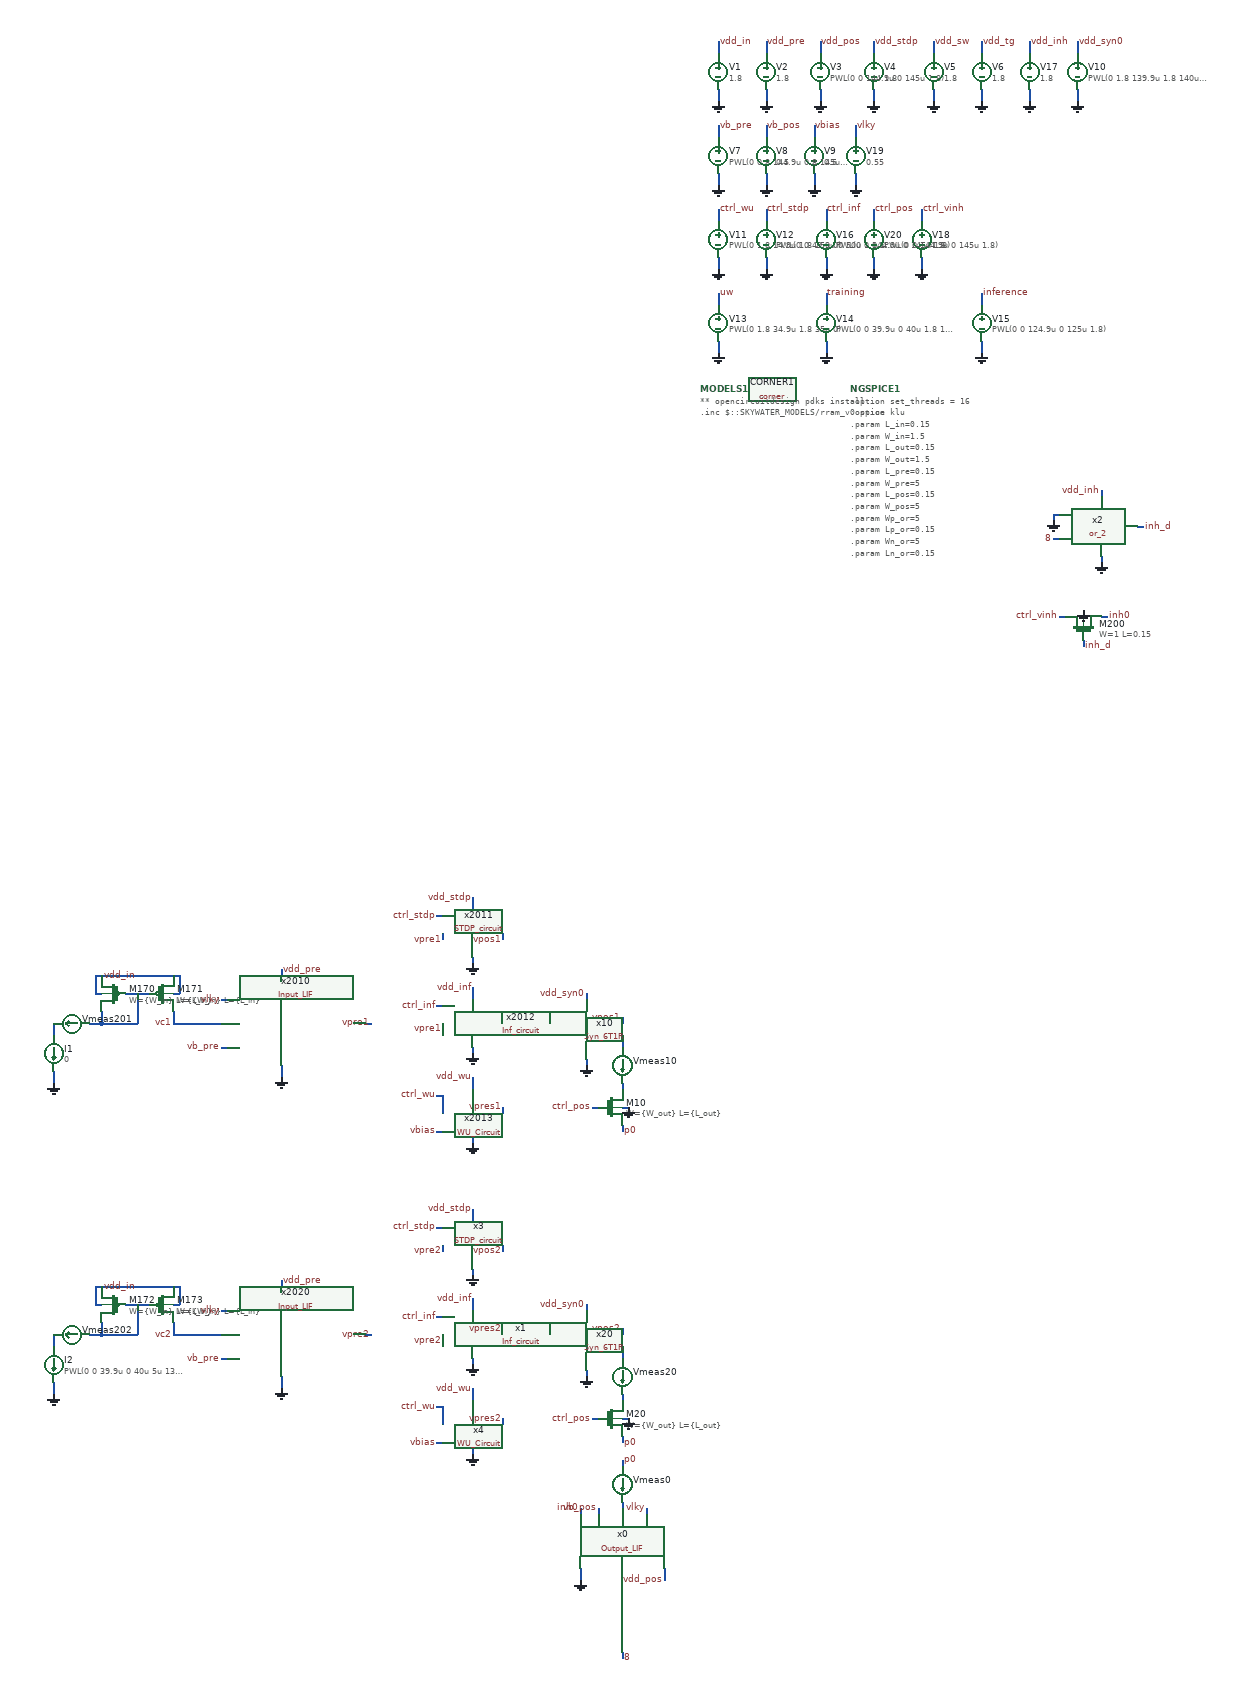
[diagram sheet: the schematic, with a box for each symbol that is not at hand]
v {xschem version=3.4.5 file_version=1.2
}
G {}
K {}
V {}
S {}
E {}
B 2 -1600 -1200 -800 -800 {flags=graph
y1=0.388
y2=2.403
ypos1=0
ypos2=2
divy=5
subdivy=1
unity=1
x1=-9.81196e-06
x2=0.000140188
divx=5
subdivx=1
xlabmag=1.0
ylabmag=1.0


dataset=-1
unitx=1
logx=0
logy=0




color="4 6 7 8 10 11 12 13 15"
node="\\"vpos1; vpos1\\"
\\"vpos2; vpos2\\"
\\"vpos3; vpos3\\"
\\"vpos4; vpos4\\"
\\"vpos5; vpos5\\"
\\"vpos6; vpos6\\"
\\"vpos7; vpos7\\"
\\"vpos8; vpos8\\"
\\"vpos9; vpos9\\""}
B 2 -800 -400 0 0 {flags=graph
y1=0
y2=1.8
ypos1=0
ypos2=2
divy=5
subdivy=1
unity=1
x1=-9.81196e-06
x2=0.000140188
divx=5
subdivx=1
xlabmag=1.0
ylabmag=1.0


dataset=-1
unitx=1
logx=0
logy=0
color="7 8 11"
node="\\"Update Weights;uw\\"
\\"Training;training\\"
\\"Inference;inference\\""}
B 2 0 -2400 800 -2000 {flags=graph
y1=-5.2e-07
y2=2.2e-05
ypos1=0
ypos2=2
divy=5
subdivy=1
unity=1
x1=-9.81196e-06
x2=0.000140188
divx=5
subdivx=1
xlabmag=1.0
ylabmag=1.0


dataset=-1
unitx=1
logx=0
logy=0






color="15 16 17"
node="\\"Ip0;i(vmeas0)\\"
\\"Ip1;i(vmeas1)\\"
\\"Ip2;i(vmeas2)\\""}
B 2 1600 -2400 2400 -2000 {flags=graph
y1=-8.4e-09
y2=1.9
ypos1=0
ypos2=2
divy=5
subdivy=1
unity=1
x1=-9.81196e-06
x2=0.000140188
divx=5
subdivx=1
xlabmag=1.0
ylabmag=1.0


dataset=-1
unitx=1
logx=0
logy=0




color=15
node=8}
B 2 -800 -1600 0 -1200 {flags=graph
y1=-0.0031
y2=1.9
ypos1=0
ypos2=2
divy=5
subdivy=1
unity=1
x1=-9.81196e-06
x2=0.000140188
divx=5
subdivx=1
xlabmag=1.0
ylabmag=1.0


dataset=-1
unitx=1
logx=0
logy=0



color="15 16 18"
node="inh0
inh1
inh2"}
B 2 -1600 -800 -800 -400 {flags=graph
y1=3
y2=4.9
ypos1=0
ypos2=2
divy=5
subdivy=1
unity=1
x1=-9.81196e-06
x2=0.000140188
divx=5
subdivx=1
xlabmag=1.0
ylabmag=1.0


dataset=-1
unitx=1
logx=0
logy=0





color="4 6 7 8 10 11 12 13 15 21 5 14 16 17 18 21"
node="\\"S10; 5 n.x10.xr1.n1#ngap -\\"
\\"S20; 5 n.x20.xr1.n1#ngap -\\"
\\"S30; 5 n.x30.xr1.n1#ngap -\\"
\\"S40; 5 n.x40.xr1.n1#ngap -\\"
\\"S50; 5 n.x50.xr1.n1#ngap -\\"
\\"S60; 5 n.x60.xr1.n1#ngap -\\"
\\"S70; 5 n.x70.xr1.n1#ngap -\\"
\\"S80; 5 n.x80.xr1.n1#ngap -\\"
\\"S90; 5 n.x90.xr1.n1#ngap -\\"
\\"S100; 5 n.x100.xr1.n1#ngap -\\"
\\"S110; 5 n.x110.xr1.n1#ngap -\\"
\\"S120; 5 n.x120.xr1.n1#ngap -\\"
\\"S130; 5 n.x130.xr1.n1#ngap -\\"
\\"S140; 5 n.x140.xr1.n1#ngap -\\"
\\"S150; 5 n.x150.xr1.n1#ngap -\\"
\\"[nm]\\""}
B 2 -800 -800 0 -400 {flags=graph
y1=-2.7e-06
y2=2.7e-06
ypos1=0
ypos2=2
divy=5
subdivy=1
unity=1
x1=-9.81196e-06
x2=0.000140188
divx=5
subdivx=1
xlabmag=1.0
ylabmag=1.0


dataset=-1
unitx=1
logx=0
logy=0





color="4 6 7 8 10 11 12 13 15 21 5 14 16 17 18 21"
node="\\"I10; i(Vmeas10)\\"
\\"I20; i(Vmeas20)\\"
\\"I30; i(Vmeas30)\\"
\\"I40; i(Vmeas40)\\"
\\"I50; i(Vmeas50)\\"
\\"I60; i(Vmeas60)\\"
\\"I70; i(Vmeas70)\\"
\\"I80; i(Vmeas80)\\"
\\"I90; i(Vmeas90)\\"
\\"I100; i(Vmeas100)\\"
\\"I110; i(Vmeas110)\\"
\\"I120; i(Vmeas120)\\"
\\"I130; i(Vmeas130)\\"
\\"I140; i(Vmeas140)\\"
\\"I150; i(Vmeas150)\\"
\\"[A]\\""}
B 2 800 -2400 1600 -2000 {flags=graph
y1=-0.0031
y2=1.9
ypos1=0
ypos2=2
divy=5
subdivy=1
unity=1
x1=-9.81196e-06
x2=0.000140188
divx=5
subdivx=1
xlabmag=1.0
ylabmag=1.0


dataset=-1
unitx=1
logx=0
logy=0



color="15 16"
node="p0
p1"}
B 2 0 -2000 800 -1600 {flags=graph
y1=0.54
y2=1.9
ypos1=0
ypos2=2
divy=5
subdivy=1
unity=1
x1=-9.81196e-06
x2=0.000140188
divx=5
subdivx=1
xlabmag=1.0
ylabmag=1.0


dataset=-1
unitx=1
logx=0
logy=0





color=4
node=vpre1}
B 2 0 -1600 800 -1200 {flags=graph
y1=0.54
y2=1.9
ypos1=0
ypos2=2
divy=5
subdivy=1
unity=1
x1=-9.81196e-06
x2=0.000140188
divx=5
subdivx=1
xlabmag=1.0
ylabmag=1.0


dataset=-1
unitx=1
logx=0
logy=0





color=4
node=vpre4}
B 2 0 -1200 800 -800 {flags=graph
y1=0.54
y2=1.9
ypos1=0
ypos2=2
divy=5
subdivy=1
unity=1
x1=-9.81196e-06
x2=0.000140188
divx=5
subdivx=1
xlabmag=1.0
ylabmag=1.0


dataset=-1
unitx=1
logx=0
logy=0





color=4
node=vpre7}
B 2 800 -2000 1600 -1600 {flags=graph
y1=-0.021
y2=2
ypos1=0
ypos2=2
divy=5
subdivy=1
unity=1
x1=-9.81196e-06
x2=0.000140188
divx=5
subdivx=1
xlabmag=1.0
ylabmag=1.0


dataset=-1
unitx=1
logx=0
logy=0





color=4
node=vpre2}
B 2 800 -1600 1600 -1200 {flags=graph
y1=0.62
y2=1.9
ypos1=0
ypos2=2
divy=5
subdivy=1
unity=1
x1=-9.81196e-06
x2=0.000140188
divx=5
subdivx=1
xlabmag=1.0
ylabmag=1.0


dataset=-1
unitx=1
logx=0
logy=0





color=4
node=vpre5}
B 2 800 -1200 1600 -800 {flags=graph
y1=0.62
y2=1.9
ypos1=0
ypos2=2
divy=5
subdivy=1
unity=1
x1=-9.81196e-06
x2=0.000140188
divx=5
subdivx=1
xlabmag=1.0
ylabmag=1.0


dataset=-1
unitx=1
logx=0
logy=0





color=4
node=vpre8}
B 2 1600 -2000 2400 -1600 {flags=graph
y1=0.54
y2=1.9
ypos1=0
ypos2=2
divy=5
subdivy=1
unity=1
x1=-9.81196e-06
x2=0.000140188
divx=5
subdivx=1
xlabmag=1.0
ylabmag=1.0


dataset=-1
unitx=1
logx=0
logy=0





color=4
node=vpre3}
B 2 1600 -1600 2400 -1200 {flags=graph
y1=0.54
y2=1.9
ypos1=0
ypos2=2
divy=5
subdivy=1
unity=1
x1=-9.81196e-06
x2=0.000140188
divx=5
subdivx=1
xlabmag=1.0
ylabmag=1.0


dataset=-1
unitx=1
logx=0
logy=0





color=4
node=vpre6}
B 2 1600 -1200 2400 -800 {flags=graph
y1=0.54
y2=1.9
ypos1=0
ypos2=2
divy=5
subdivy=1
unity=1
x1=-9.81196e-06
x2=0.000140188
divx=5
subdivx=1
xlabmag=1.0
ylabmag=1.0


dataset=-1
unitx=1
logx=0
logy=0





color=4
node=vpre9}
B 2 0 -800 800 -400 {flags=graph
y1=0.54
y2=1.9
ypos1=0
ypos2=2
divy=5
subdivy=1
unity=1
x1=-9.81196e-06
x2=0.000140188
divx=5
subdivx=1
xlabmag=1.0
ylabmag=1.0


dataset=-1
unitx=1
logx=0
logy=0





color=4
node=vpre10}
B 2 0 -400 800 0 {flags=graph
y1=0.54
y2=1.9
ypos1=0
ypos2=2
divy=5
subdivy=1
unity=1
x1=-9.81196e-06
x2=0.000140188
divx=5
subdivx=1
xlabmag=1.0
ylabmag=1.0


dataset=-1
unitx=1
logx=0
logy=0





color=4
node=vpre13}
B 2 800 -800 1600 -400 {flags=graph
y1=0.62
y2=1.9
ypos1=0
ypos2=2
divy=5
subdivy=1
unity=1
x1=-9.81196e-06
x2=0.000140188
divx=5
subdivx=1
xlabmag=1.0
ylabmag=1.0


dataset=-1
unitx=1
logx=0
logy=0





color=4
node=vpre11}
B 2 800 -400 1600 0 {flags=graph
y1=0.62
y2=1.9
ypos1=0
ypos2=2
divy=5
subdivy=1
unity=1
x1=-9.81196e-06
x2=0.000140188
divx=5
subdivx=1
xlabmag=1.0
ylabmag=1.0


dataset=-1
unitx=1
logx=0
logy=0





color=4
node=vpre14}
B 2 1600 -800 2400 -400 {flags=graph
y1=0.54
y2=1.9
ypos1=0
ypos2=2
divy=5
subdivy=1
unity=1
x1=-9.81196e-06
x2=0.000140188
divx=5
subdivx=1
xlabmag=1.0
ylabmag=1.0


dataset=-1
unitx=1
logx=0
logy=0





color=4
node=vpre12}
B 2 1600 -400 2400 0 {flags=graph
y1=0.54
y2=1.9
ypos1=0
ypos2=2
divy=5
subdivy=1
unity=1
x1=-9.81196e-06
x2=0.000140188
divx=5
subdivx=1
xlabmag=1.0
ylabmag=1.0


dataset=-1
unitx=1
logx=0
logy=0





color=4
node=vpre15}
B 2 -800 -1200 0 -800 {flags=graph
y1=-7.4e-07
y2=7.7e-06
ypos1=0
ypos2=2
divy=5
subdivy=1
unity=1
x1=-9.81196e-06
x2=0.000140188
divx=5
subdivx=1
xlabmag=1.0
ylabmag=1.0


dataset=-1
unitx=1
logx=0
logy=0




color=15
node=i(Vmeas0)}
B 2 -1600 -400 -800 0 {flags=graph
y1=-0.047
y2=1.9
ypos1=0
ypos2=2
divy=5
subdivy=1
unity=1
x1=-9.81196e-06
x2=0.000140188
divx=5
subdivx=1
xlabmag=1.0
ylabmag=1.0


dataset=-1
unitx=1
logx=0
logy=0




color="4 6 7 8 10 11 12 13 15"
node="\\"vpres1; vpres1\\"
\\"vpres2; vpres2\\"
\\"vpres3; vpres3\\"
\\"vpres4; vpres4\\"
\\"vpres5; vpres5\\"
\\"vpres6; vpres6\\"
\\"vpres7; vpres7\\"
\\"vpres8; vpres8\\"
\\"vpres9; vpres9\\""}
B 2 -1600 -1600 -800 -1200 {flags=graph
y1=0.019
y2=2.2
ypos1=0
ypos2=2
divy=5
subdivy=1
unity=1
x1=-9.81196e-06
x2=0.000140188
divx=5
subdivx=1
xlabmag=1.0
ylabmag=1.0


dataset=-1
unitx=1
logx=0
logy=0




color="4 6 7 8 10 11 12 13 15"
node="\\"vpre1; vpres1\\"
\\"vpre2; vpres2\\"
\\"vpre3; vpres3\\"
\\"vpre4; vpres4\\"
\\"vpre5; vpres5\\"
\\"vpre6; vpres6\\"
\\"vpre7; vpres7\\"
\\"vpre8; vpres8\\"
\\"vpre9; vpre9s\\""}
N -1580 -2620 -1580 -2600 {
lab=GND}
N -1580 -2700 -1580 -2680 {
lab=vdd_in}
N -1500 -2620 -1500 -2600 {
lab=GND}
N -1500 -2700 -1500 -2680 {
lab=vdd_pre}
N -2310 -470 -2310 -450 {
lab=GND}
N -2310 -630 -2310 -610 {
lab=vdd_pre}
N -2690 -460 -2690 -440 {
lab=GND}
N -2490 -560 -2490 -540 {
lab=vc2}
N -2490 -590 -2480 -590 {
lab=vdd_in}
N -2480 -620 -2480 -590 {
lab=vdd_in}
N -2490 -620 -2480 -620 {
lab=vdd_in}
N -2570 -590 -2530 -590 {
lab=#net1}
N -2610 -620 -2490 -620 {
lab=vdd_in}
N -2620 -590 -2610 -590 {
lab=vdd_in}
N -2620 -620 -2620 -590 {
lab=vdd_in}
N -2620 -620 -2610 -620 {
lab=vdd_in}
N -2610 -560 -2610 -540 {
lab=#net1}
N -2610 -540 -2550 -540 {
lab=#net1}
N -2550 -590 -2550 -540 {
lab=#net1}
N -2690 -540 -2690 -520 {
lab=#net2}
N -1320 -2620 -1320 -2600 {
lab=GND}
N -1320 -2700 -1320 -2680 {
lab=vdd_stdp}
N -1800 -1000 -1800 -990 {
lab=GND}
N -1800 -1110 -1800 -1100 {
lab=vdd_syn0}
N -1740 -920 -1730 -920 {
lab=GND}
N -1740 -890 -1740 -880 {
lab=p0}
N -1740 -260 -1740 -250 {
lab=#net3}
N -1740 -330 -1740 -320 {
lab=p0}
N -1740 -10 -1740 0 {
lab=8}
N -1580 -2200 -1580 -2180 {
lab=GND}
N -1580 -2280 -1580 -2260 {
lab=uw}
N -1400 -2200 -1400 -2180 {
lab=GND}
N -1400 -2280 -1400 -2260 {
lab=training}
N -2170 -540 -2160 -540 {
lab=vpre2}
N -1810 -150 -1810 -130 {
lab=GND}
N -1670 -150 -1670 -130 {
lab=vdd_pos}
N -1140 -2200 -1140 -2180 {
lab=GND}
N -1140 -2280 -1140 -2260 {
lab=inference}
N -2630 -540 -2610 -540 {
lab=#net1}
N -1580 -2340 -1580 -2320 {
lab=GND}
N -1580 -2420 -1580 -2400 {
lab=ctrl_wu}
N -1500 -2340 -1500 -2320 {
lab=GND}
N -1500 -2420 -1500 -2400 {
lab=ctrl_stdp}
N -1420 -2480 -1420 -2460 {
lab=GND}
N -1420 -2560 -1420 -2540 {
lab=vbias}
N -1410 -2620 -1410 -2600 {
lab=GND}
N -1410 -2700 -1410 -2680 {
lab=vdd_pos}
N -1220 -2620 -1220 -2600 {
lab=GND}
N -1220 -2700 -1220 -2680 {
lab=vdd_sw}
N -1140 -2620 -1140 -2600 {
lab=GND}
N -1140 -2700 -1140 -2680 {
lab=vdd_tg}
N -1580 -2480 -1580 -2460 {
lab=GND}
N -1580 -2560 -1580 -2540 {
lab=vb_pre}
N -1500 -2480 -1500 -2460 {
lab=GND}
N -1500 -2560 -1500 -2540 {
lab=vb_pos}
N -1860 -1070 -1860 -1060 {
lab=vpres1}
N -1740 -1070 -1740 -1060 {
lab=vpos1}
N -2310 -990 -2310 -970 {
lab=GND}
N -2310 -1150 -2310 -1130 {
lab=vdd_pre}
N -2690 -980 -2690 -960 {
lab=GND}
N -2490 -1080 -2490 -1060 {
lab=vc1}
N -2490 -1110 -2480 -1110 {
lab=vdd_in}
N -2480 -1140 -2480 -1110 {
lab=vdd_in}
N -2490 -1140 -2480 -1140 {
lab=vdd_in}
N -2570 -1110 -2530 -1110 {
lab=#net4}
N -2610 -1140 -2490 -1140 {
lab=vdd_in}
N -2620 -1110 -2610 -1110 {
lab=vdd_in}
N -2620 -1140 -2620 -1110 {
lab=vdd_in}
N -2620 -1140 -2610 -1140 {
lab=vdd_in}
N -2610 -1080 -2610 -1060 {
lab=#net4}
N -2610 -1060 -2550 -1060 {
lab=#net4}
N -2550 -1110 -2550 -1060 {
lab=#net4}
N -2690 -1060 -2690 -1040 {
lab=#net5}
N -1800 -480 -1800 -470 {
lab=GND}
N -1800 -590 -1800 -580 {
lab=vdd_syn0}
N -1990 -1170 -1990 -1160 {
lab=GND}
N -1740 -400 -1730 -400 {
lab=GND}
N -1740 -370 -1740 -360 {
lab=p0}
N -2170 -1060 -2160 -1060 {
lab=vpre1}
N -2630 -1060 -2610 -1060 {
lab=#net4}
N -1990 -870 -1990 -860 {
lab=GND}
N -1940 -920 -1940 -910 {
lab=vpres1}
N -1990 -1020 -1990 -1010 {
lab=GND}
N -2040 -1060 -2040 -1050 {
lab=vpre1}
N -2040 -1210 -2040 -1200 {
lab=vpre1}
N -1940 -1210 -1940 -1200 {
lab=vpos1}
N -1940 -1070 -1940 -1060 {
lab=vpres1}
N -1860 -550 -1860 -540 {
lab=vpres2}
N -1740 -550 -1740 -540 {
lab=vpos2}
N -1790 -400 -1780 -400 {
lab=ctrl_pos}
N -1790 -920 -1780 -920 {
lab=ctrl_pos}
N -1400 -2340 -1400 -2320 {
lab=GND}
N -1400 -2420 -1400 -2400 {
lab=ctrl_inf}
N -1060 -2620 -1060 -2600 {
lab=GND}
N -1060 -2700 -1060 -2680 {
lab=vdd_inh}
N -940 -1950 -940 -1940 {
lab=vdd_inh}
N -1240 -2340 -1240 -2320 {
lab=GND}
N -1240 -2420 -1240 -2400 {
lab=ctrl_vinh}
N -940 -1840 -940 -1830 {
lab=GND}
N -880 -1890 -870 -1890 {
lab=inh_d}
N -940 -1740 -930 -1740 {
lab=inh0}
N -970 -1750 -970 -1740 {
lab=GND}
N -970 -1700 -970 -1690 {
lab=inh_d}
N -1010 -1740 -1000 -1740 {
lab=ctrl_vinh}
N -1350 -2480 -1350 -2460 {
lab=GND}
N -1350 -2560 -1350 -2540 {
lab=vlky}
N -2490 -1060 -2410 -1060 {
lab=vc1}
N -2410 -1100 -2400 -1100 {
lab=vlky}
N -2410 -1020 -2400 -1020 {
lab=vb_pre}
N -2410 -580 -2400 -580 {
lab=vlky}
N -2490 -540 -2410 -540 {
lab=vc2}
N -2410 -500 -2400 -500 {
lab=vb_pre}
N -1810 -250 -1810 -240 {
lab=inh0}
N -1780 -250 -1780 -240 {
lab=vb_pos}
N -1700 -250 -1700 -240 {
lab=vlky}
N -980 -2620 -980 -2600 {
lab=GND}
N -980 -2700 -980 -2680 {
lab=vdd_syn0}
N -2050 -880 -2040 -880 {
lab=vbias}
N -1740 -1040 -1740 -1020 {
lab=#net6}
N -1740 -960 -1740 -950 {
lab=#net7}
N -1740 -520 -1740 -500 {
lab=#net8}
N -1740 -440 -1740 -430 {
lab=#net9}
N -1020 -1870 -1010 -1870 {
lab=8}
N -1020 -1910 -1020 -1900 {
lab=GND}
N -1020 -1910 -1010 -1910 {
lab=GND}
N -2050 -1240 -2040 -1240 {
lab=ctrl_stdp}
N -2050 -1090 -2040 -1090 {
lab=ctrl_inf}
N -1990 -970 -1990 -950 {
lab=vdd_wu}
N -1990 -1120 -1990 -1100 {
lab=vdd_inf}
N -1990 -1270 -1990 -1250 {
lab=vdd_stdp}
N -2050 -940 -2040 -940 {
lab=ctrl_wu}
N -2040 -940 -2040 -910 {
lab=ctrl_wu}
N -1320 -2340 -1320 -2320 {
lab=GND}
N -1320 -2420 -1320 -2400 {
lab=ctrl_pos}
N -1990 -650 -1990 -640 {
lab=GND}
N -1990 -350 -1990 -340 {
lab=GND}
N -1940 -400 -1940 -390 {
lab=vpres2}
N -1990 -500 -1990 -490 {
lab=GND}
N -2040 -540 -2040 -530 {
lab=vpre2}
N -2040 -690 -2040 -680 {
lab=vpre2}
N -1940 -690 -1940 -680 {
lab=vpos2}
N -1940 -550 -1940 -540 {
lab=vpres2}
N -2050 -360 -2040 -360 {
lab=vbias}
N -2050 -720 -2040 -720 {
lab=ctrl_stdp}
N -2050 -570 -2040 -570 {
lab=ctrl_inf}
N -1990 -450 -1990 -430 {
lab=vdd_wu}
N -1990 -600 -1990 -580 {
lab=vdd_inf}
N -1990 -750 -1990 -730 {
lab=vdd_stdp}
N -2050 -420 -2040 -420 {
lab=ctrl_wu}
N -2040 -420 -2040 -390 {
lab=ctrl_wu}
C {devices/vsource.sym} -1580 -2650 0 0 {name=V1 value=1.8}
C {devices/gnd.sym} -1580 -2600 0 0 {name=l6 lab=GND}
C {devices/vsource.sym} -1500 -2650 0 0 {name=V2 value=1.8}
C {devices/gnd.sym} -1500 -2600 0 0 {name=l9 lab=GND}
C {devices/lab_pin.sym} -1500 -2700 2 0 {name=p9 sig_type=std_logic lab=vdd_pre}
C {devices/gnd.sym} -2310 -450 0 0 {name=l13 lab=GND}
C {devices/lab_pin.sym} -2410 -500 0 0 {name=p13 sig_type=std_logic lab=vb_pre}
C {devices/isource.sym} -2690 -490 0 0 {name=I2 value="PWL(0 0 39.9u 0 40u 5u 139.9u 5u 140u 0 144.999u 0 145u 5u)"}
C {devices/gnd.sym} -2690 -440 0 0 {name=l20 lab=GND}
C {sky130_fd_pr/pfet_01v8.sym} -2510 -590 0 0 {name=M173
L=\{L_in\}
W=\{W_in\}
nf=1
mult=1
ad="'int((nf+1)/2) * W/nf * 0.29'" 
pd="'2*int((nf+1)/2) * (W/nf + 0.29)'"
as="'int((nf+2)/2) * W/nf * 0.29'" 
ps="'2*int((nf+2)/2) * (W/nf + 0.29)'"
nrd="'0.29 / W'" nrs="'0.29 / W'"
sa=0 sb=0 sd=0
model=pfet_01v8
spiceprefix=X
}
C {sky130_fd_pr/pfet_01v8.sym} -2590 -590 0 1 {name=M172
L=\{L_in\}
W=\{W_in\}
nf=1
mult=1
ad="'int((nf+1)/2) * W/nf * 0.29'" 
pd="'2*int((nf+1)/2) * (W/nf + 0.29)'"
as="'int((nf+2)/2) * W/nf * 0.29'" 
ps="'2*int((nf+2)/2) * (W/nf + 0.29)'"
nrd="'0.29 / W'" nrs="'0.29 / W'"
sa=0 sb=0 sd=0
model=pfet_01v8
spiceprefix=X
}
C {sky130_fd_pr/corner.sym} -1490 -2120 0 0 {name=CORNER1 only_toplevel=true corner=tt}
C {devices/code.sym} -1610 -2120 0 0 {name=MODELS1
only_toplevel=true
format="tcleval( @value )"
value="
** opencircuitdesign pdks install
.inc $::SKYWATER_MODELS/rram_v0.spice
"
spice_ignore=false}
C {devices/code_shown.sym} -1360 -2120 0 0 {name=NGSPICE1
only_toplevel=true
value="
.option set_threads = 16
.option klu
.param L_in=0.15
.param W_in=1.5
.param L_out=0.15
.param W_out=1.5
.param L_pre=0.15
.param W_pre=5
.param L_pos=0.15
.param W_pos=5
.param Wp_or=5
.param Lp_or=0.15
.param Wn_or=5
.param Ln_or=0.15
.control
	save all
	tran 10n 50u
	write SNN_2x1optimized_tb.raw
	*wrdata SNN_15x1_tbv1.ssv v(8)
.endc
" }
C {devices/launcher.sym} -1520 -1735 0 0 {name=h1
descr="load 1" 
tclcommand="xschem raw_read $netlist_dir/SNN_2x1optimized_tb.raw tran"
}
C {devices/lab_pin.sym} -2490 -540 0 0 {name=p10 sig_type=std_logic lab=vc2}
C {devices/vsource.sym} -1320 -2650 0 0 {name=V4 value=1.8}
C {devices/gnd.sym} -1320 -2600 0 0 {name=l29 lab=GND}
C {devices/lab_pin.sym} -1320 -2700 2 0 {name=p16 sig_type=std_logic lab=vdd_stdp}
C {devices/gnd.sym} -1800 -990 0 0 {name=l39 lab=GND}
C {devices/lab_pin.sym} -1860 -1070 1 0 {name=p26 sig_type=std_logic lab=vpres1}
C {devices/lab_pin.sym} -1740 -1070 1 0 {name=p27 sig_type=std_logic lab=vpos1}
C {devices/ammeter.sym} -1740 -990 0 0 {name=Vmeas10 savecurrent=true}
C {sky130_fd_pr/nfet_01v8.sym} -1760 -920 0 0 {name=M10
L=\{L_out\}
W=\{W_out\}
nf=1 
mult=1
ad="'int((nf+1)/2) * W/nf * 0.29'" 
pd="'2*int((nf+1)/2) * (W/nf + 0.29)'"
as="'int((nf+2)/2) * W/nf * 0.29'" 
ps="'2*int((nf+2)/2) * (W/nf + 0.29)'"
nrd="'0.29 / W'" nrs="'0.29 / W'"
sa=0 sb=0 sd=0
model=nfet_01v8
spiceprefix=X
}
C {devices/gnd.sym} -1730 -920 3 0 {name=l4 lab=GND}
C {devices/lab_pin.sym} -1740 -880 2 0 {name=p46 sig_type=std_logic lab=p0}
C {devices/lab_pin.sym} -1780 -250 1 0 {name=p59 sig_type=std_logic lab=vb_pos}
C {devices/gnd.sym} -1810 -130 0 0 {name=l63 lab=GND}
C {devices/ammeter.sym} -1740 -290 0 0 {name=Vmeas0 savecurrent=true}
C {devices/lab_pin.sym} -1740 -330 2 0 {name=p60 sig_type=std_logic lab=p0}
C {devices/lab_pin.sym} -1740 0 2 0 {name=p61 sig_type=std_logic lab=8}
C {devices/vsource.sym} -1580 -2230 0 0 {name=V13 value="PWL(0 1.8 34.9u 1.8 35u 0)"}
C {devices/gnd.sym} -1580 -2180 0 0 {name=l67 lab=GND}
C {devices/lab_pin.sym} -1580 -2280 2 0 {name=p65 sig_type=std_logic lab=uw}
C {devices/vsource.sym} -1400 -2230 0 0 {name=V14 value="PWL(0 0 39.9u 0 40u 1.8 119.9u 1.8 120u 0)"}
C {devices/gnd.sym} -1400 -2180 0 0 {name=l68 lab=GND}
C {devices/lab_pin.sym} -1400 -2280 2 0 {name=p66 sig_type=std_logic lab=training}
C {devices/vsource.sym} -1140 -2230 0 0 {name=V15 value="PWL(0 0 124.9u 0 125u 1.8)"}
C {devices/gnd.sym} -1140 -2180 0 0 {name=l69 lab=GND}
C {devices/lab_pin.sym} -1140 -2280 2 0 {name=p73 sig_type=std_logic lab=inference}
C {devices/ammeter.sym} -2660 -540 1 0 {name=Vmeas202 savecurrent=true}
C {devices/vsource.sym} -1580 -2370 0 0 {name=V11 value="PWL(0 1.8 14.9u 1.8 15u 0)"}
C {devices/gnd.sym} -1580 -2320 0 0 {name=l72 lab=GND}
C {devices/lab_pin.sym} -1580 -2420 2 0 {name=p75 sig_type=std_logic lab=ctrl_wu}
C {devices/vsource.sym} -1500 -2370 0 0 {name=V12 value="PWL(0 0 49.9u 0 50u 1.8 139.9u 1.8 140u 0)"}
C {devices/gnd.sym} -1500 -2320 0 0 {name=l35 lab=GND}
C {devices/lab_pin.sym} -1500 -2420 2 0 {name=p17 sig_type=std_logic lab=ctrl_stdp}
C {devices/vsource.sym} -1420 -2510 0 0 {name=V9 value=0.5}
C {devices/gnd.sym} -1420 -2460 0 0 {name=l75 lab=GND}
C {devices/lab_pin.sym} -1420 -2560 2 0 {name=p82 sig_type=std_logic lab=vbias}
C {devices/vsource.sym} -1410 -2650 0 0 {name=V3 value="PWL(0 0 144.9u 0 145u 1.8)"}
C {devices/gnd.sym} -1410 -2600 0 0 {name=l5 lab=GND}
C {devices/lab_pin.sym} -1410 -2700 2 0 {name=p6 sig_type=std_logic lab=vdd_pos}
C {devices/vsource.sym} -1220 -2650 0 0 {name=V5 value=1.8
*"PWL(0 1.8 34.9u 1.8 35u 0)"}
C {devices/gnd.sym} -1220 -2600 0 0 {name=l1 lab=GND}
C {devices/lab_pin.sym} -1220 -2700 2 0 {name=p1 sig_type=std_logic lab=vdd_sw}
C {devices/vsource.sym} -1140 -2650 0 0 {name=V6 value=1.8}
C {devices/gnd.sym} -1140 -2600 0 0 {name=l2 lab=GND}
C {devices/lab_pin.sym} -1140 -2700 2 0 {name=p3 sig_type=std_logic lab=vdd_tg}
C {devices/vsource.sym} -1580 -2510 0 0 {name=V7 value="PWL(0 0.8 144.9u 0.8 145u 0.45)"
*0.55}
C {devices/gnd.sym} -1580 -2460 0 0 {name=l10 lab=GND}
C {devices/lab_pin.sym} -1580 -2560 2 0 {name=p8 sig_type=std_logic lab=vb_pre}
C {devices/vsource.sym} -1500 -2510 0 0 {name=V8 value=0.5}
C {devices/gnd.sym} -1500 -2460 0 0 {name=l11 lab=GND}
C {devices/lab_pin.sym} -1500 -2560 2 0 {name=p11 sig_type=std_logic lab=vb_pos}
C {devices/lab_pin.sym} -2310 -630 2 0 {name=p4 sig_type=std_logic lab=vdd_pre}
C {devices/lab_pin.sym} -1670 -130 3 0 {name=p12 sig_type=std_logic lab=vdd_pos}
C {devices/lab_pin.sym} -1580 -2700 2 0 {name=p21 sig_type=std_logic lab=vdd_in}
C {devices/lab_pin.sym} -2550 -620 1 0 {name=p40 sig_type=std_logic lab=vdd_in}
C {devices/gnd.sym} -2310 -970 0 0 {name=l12 lab=GND}
C {devices/lab_pin.sym} -2410 -1020 0 0 {name=p23 sig_type=std_logic lab=vb_pre}
C {devices/isource.sym} -2690 -1010 0 0 {name=I1 value=0}
C {devices/gnd.sym} -2690 -960 0 0 {name=l14 lab=GND}
C {sky130_fd_pr/pfet_01v8.sym} -2510 -1110 0 0 {name=M171
L=\{L_in\}
W=\{W_in\}
nf=1
mult=1
ad="'int((nf+1)/2) * W/nf * 0.29'" 
pd="'2*int((nf+1)/2) * (W/nf + 0.29)'"
as="'int((nf+2)/2) * W/nf * 0.29'" 
ps="'2*int((nf+2)/2) * (W/nf + 0.29)'"
nrd="'0.29 / W'" nrs="'0.29 / W'"
sa=0 sb=0 sd=0
model=pfet_01v8
spiceprefix=X
}
C {sky130_fd_pr/pfet_01v8.sym} -2590 -1110 0 1 {name=M170
L=\{L_in\}
W=\{W_in\}
nf=1
mult=1
ad="'int((nf+1)/2) * W/nf * 0.29'" 
pd="'2*int((nf+1)/2) * (W/nf + 0.29)'"
as="'int((nf+2)/2) * W/nf * 0.29'" 
ps="'2*int((nf+2)/2) * (W/nf + 0.29)'"
nrd="'0.29 / W'" nrs="'0.29 / W'"
sa=0 sb=0 sd=0
model=pfet_01v8
spiceprefix=X
}
C {devices/lab_pin.sym} -2490 -1060 0 0 {name=p25 sig_type=std_logic lab=vc1}
C {devices/gnd.sym} -1800 -470 0 0 {name=l15 lab=GND}
C {devices/lab_pin.sym} -1860 -550 1 0 {name=p29 sig_type=std_logic lab=vpres2}
C {devices/lab_pin.sym} -1740 -550 1 0 {name=p30 sig_type=std_logic lab=vpos2}
C {devices/gnd.sym} -1990 -1160 0 0 {name=l16 lab=GND}
C {devices/lab_pin.sym} -1940 -1200 3 0 {name=p31 sig_type=std_logic lab=vpos1}
C {devices/lab_pin.sym} -2040 -1200 3 0 {name=p32 sig_type=std_logic lab=vpre1}
C {devices/ammeter.sym} -1740 -470 0 0 {name=Vmeas20 savecurrent=true}
C {sky130_fd_pr/nfet_01v8.sym} -1760 -400 0 0 {name=M20
L=\{L_out\}
W=\{W_out\}
nf=1 
mult=1
ad="'int((nf+1)/2) * W/nf * 0.29'" 
pd="'2*int((nf+1)/2) * (W/nf + 0.29)'"
as="'int((nf+2)/2) * W/nf * 0.29'" 
ps="'2*int((nf+2)/2) * (W/nf + 0.29)'"
nrd="'0.29 / W'" nrs="'0.29 / W'"
sa=0 sb=0 sd=0
model=nfet_01v8
spiceprefix=X
}
C {devices/gnd.sym} -1730 -400 3 0 {name=l17 lab=GND}
C {devices/lab_pin.sym} -1740 -360 2 0 {name=p34 sig_type=std_logic lab=p0}
C {devices/lab_pin.sym} -1940 -920 1 0 {name=p35 sig_type=std_logic lab=vpres1}
C {devices/lab_pin.sym} -2160 -1060 3 0 {name=p37 sig_type=std_logic lab=vpre1}
C {devices/ammeter.sym} -2660 -1060 1 0 {name=Vmeas201 savecurrent=true}
C {devices/gnd.sym} -1990 -860 0 0 {name=l18 lab=GND}
C {devices/lab_pin.sym} -1940 -1070 1 0 {name=p39 sig_type=std_logic lab=vpres1}
C {devices/lab_pin.sym} -2040 -1050 3 0 {name=p41 sig_type=std_logic lab=vpre1}
C {devices/lab_pin.sym} -2050 -1090 0 0 {name=p42 sig_type=std_logic lab=ctrl_inf}
C {devices/gnd.sym} -1990 -1010 0 0 {name=l19 lab=GND}
C {devices/lab_pin.sym} -2310 -1150 2 0 {name=p43 sig_type=std_logic lab=vdd_pre}
C {devices/lab_pin.sym} -1990 -1270 0 0 {name=p45 sig_type=std_logic lab=vdd_stdp}
C {devices/lab_pin.sym} -1990 -970 0 0 {name=p47 sig_type=std_logic lab=vdd_wu}
C {devices/lab_pin.sym} -1990 -1120 0 0 {name=p48 sig_type=std_logic lab=vdd_inf}
C {devices/lab_pin.sym} -2550 -1140 1 0 {name=p50 sig_type=std_logic lab=vdd_in}
C {devices/lab_pin.sym} -1790 -400 0 0 {name=p76 sig_type=std_logic lab=ctrl_pos}
C {devices/lab_pin.sym} -1790 -920 0 0 {name=p78 sig_type=std_logic lab=ctrl_pos}
C {devices/vsource.sym} -1400 -2370 0 0 {name=V16 value="PWL(0 0 144.9u 0 145u 1.8)"}
C {devices/gnd.sym} -1400 -2320 0 0 {name=l25 lab=GND}
C {devices/lab_pin.sym} -1400 -2420 2 0 {name=p71 sig_type=std_logic lab=ctrl_inf}
C {devices/vsource.sym} -1060 -2650 0 0 {name=V17 value=1.8}
C {devices/gnd.sym} -1060 -2600 0 0 {name=l26 lab=GND}
C {devices/lab_pin.sym} -1060 -2700 2 0 {name=p80 sig_type=std_logic lab=vdd_inh}
C {devices/gnd.sym} -940 -1830 0 0 {name=l27 lab=GND}
C {devices/lab_pin.sym} -940 -1950 0 0 {name=p81 sig_type=std_logic lab=vdd_inh}
C {devices/lab_pin.sym} -1810 -250 1 0 {name=p87 sig_type=std_logic lab=inh0}
C {devices/vsource.sym} -1240 -2370 0 0 {name=V18 value=1.8}
C {devices/gnd.sym} -1240 -2320 0 0 {name=l28 lab=GND}
C {devices/lab_pin.sym} -1240 -2420 2 0 {name=p88 sig_type=std_logic lab=ctrl_vinh}
C {devices/lab_pin.sym} -870 -1890 2 0 {name=p91 sig_type=std_logic lab=inh_d}
C {devices/lab_pin.sym} -930 -1740 2 0 {name=p94 sig_type=std_logic lab=inh0}
C {sky130_fd_pr/nfet_01v8.sym} -970 -1720 3 0 {name=M200
L=0.15
W=1
nf=1 
mult=1
ad="'int((nf+1)/2) * W/nf * 0.29'" 
pd="'2*int((nf+1)/2) * (W/nf + 0.29)'"
as="'int((nf+2)/2) * W/nf * 0.29'" 
ps="'2*int((nf+2)/2) * (W/nf + 0.29)'"
nrd="'0.29 / W'" nrs="'0.29 / W'"
sa=0 sb=0 sd=0
model=nfet_01v8
spiceprefix=X
}
C {devices/gnd.sym} -970 -1750 2 0 {name=l31 lab=GND}
C {devices/lab_pin.sym} -970 -1690 2 0 {name=p72 sig_type=std_logic lab=inh_d}
C {devices/lab_pin.sym} -1010 -1740 0 0 {name=p85 sig_type=std_logic lab=ctrl_vinh}
C {devices/vsource.sym} -1350 -2510 0 0 {name=V19 value=0.55}
C {devices/gnd.sym} -1350 -2460 0 0 {name=l36 lab=GND}
C {devices/lab_pin.sym} -1350 -2560 2 0 {name=p95 sig_type=std_logic lab=vlky}
C {devices/lab_pin.sym} -2410 -1100 1 0 {name=p96 sig_type=std_logic lab=vlky}
C {devices/lab_pin.sym} -2410 -580 1 0 {name=p97 sig_type=std_logic lab=vlky}
C {devices/lab_pin.sym} -1700 -250 1 0 {name=p56 sig_type=std_logic lab=vlky}
C {devices/vsource.sym} -980 -2650 0 0 {name=V10 value="PWL(0 1.8 139.9u 1.8 140u 0 144.9u 0 145u 1.8)"}
C {devices/gnd.sym} -980 -2600 0 0 {name=l3 lab=GND}
C {devices/lab_pin.sym} -980 -2700 2 0 {name=p7 sig_type=std_logic lab=vdd_syn0}
C {devices/lab_pin.sym} -2050 -880 0 0 {name=p100 sig_type=std_logic lab=vbias}
C {devices/lab_pin.sym} -1020 -1870 0 0 {name=p105 sig_type=std_logic lab=8}
C {devices/lab_pin.sym} -2160 -540 3 0 {name=p5 sig_type=std_logic lab=vpre2}
C {devices/launcher.sym} -1510 -1815 0 0 {name=h2
descr="no lag" 
tclcommand="xschem raw_read $netlist_dir/SNN_2x2_tb.raw tran"
}
C {/home/ricardo/RATT_repos/Proyectos_xschem/SNN/Input_LIF.sym} -2310 -540 0 0 {name=x2020}
C {/home/ricardo/RATT_repos/Proyectos_xschem/SNN/Input_LIF.sym} -2310 -1060 0 0 {name=x2010}
C {/home/ricardo/RATT_repos/Proyectos_xschem/SNN/Output_LIF.sym} -1740 -150 1 0 {name=x0}
C {/home/ricardo/RATT_repos/Proyectos_xschem/SNN/Syn_6T1R.sym} -1740 -880 0 0 {name=x10}
C {/home/ricardo/RATT_repos/Proyectos_xschem/SNN/Syn_6T1R.sym} -1740 -360 0 0 {name=x20}
C {/home/ricardo/RATT_repos/Proyectos_xschem/inhibitory/or_2.sym} -940 -1890 0 0 {name=x2}
C {devices/lab_pin.sym} -1800 -1110 1 0 {name=p63 sig_type=std_logic lab=vdd_syn0}
C {devices/lab_pin.sym} -1800 -590 1 0 {name=p70 sig_type=std_logic lab=vdd_syn0}
C {devices/gnd.sym} -1020 -1900 0 0 {name=l7 lab=GND}
C {devices/launcher.sym} -1520 -1675 0 0 {name=h3
descr="load 8" 
tclcommand="xschem raw_read $netlist_dir/SNN_15x1_tb.raw tran"
}
C {devices/lab_pin.sym} -2050 -1240 0 0 {name=p15 sig_type=std_logic lab=ctrl_stdp}
C {/home/ricardo/RATT_repos/Proyectos_xschem/SNN/Inf_circuit.sym} -1990 -1060 0 0 {name=x2012}
C {/home/ricardo/RATT_repos/Proyectos_xschem/SNN/STDP_circuit.sym} -1990 -1210 0 0 {name=x2011}
C {/home/ricardo/RATT_repos/Proyectos_xschem/SNN/WU_Circuit.sym} -1990 -910 0 0 {name=x2013}
C {devices/lab_pin.sym} -2050 -940 0 0 {name=p36 sig_type=std_logic lab=ctrl_wu}
C {devices/vsource.sym} -1320 -2370 0 0 {name=V20 value="PWL(0 0 144.9u 0 145u 1.8)"}
C {devices/gnd.sym} -1320 -2320 0 0 {name=l8 lab=GND}
C {devices/lab_pin.sym} -1320 -2420 2 0 {name=p38 sig_type=std_logic lab=ctrl_pos}
C {devices/gnd.sym} -1990 -640 0 0 {name=l21 lab=GND}
C {devices/lab_pin.sym} -1940 -680 3 0 {name=p2 sig_type=std_logic lab=vpos2}
C {devices/gnd.sym} -1990 -340 0 0 {name=l22 lab=GND}
C {devices/lab_pin.sym} -2050 -570 0 0 {name=p22 sig_type=std_logic lab=ctrl_inf}
C {devices/gnd.sym} -1990 -490 0 0 {name=l23 lab=GND}
C {devices/lab_pin.sym} -1990 -750 0 0 {name=p24 sig_type=std_logic lab=vdd_stdp}
C {devices/lab_pin.sym} -1990 -450 0 0 {name=p28 sig_type=std_logic lab=vdd_wu}
C {devices/lab_pin.sym} -1990 -600 0 0 {name=p33 sig_type=std_logic lab=vdd_inf}
C {devices/lab_pin.sym} -2050 -360 0 0 {name=p44 sig_type=std_logic lab=vbias}
C {devices/lab_pin.sym} -2050 -720 0 0 {name=p49 sig_type=std_logic lab=ctrl_stdp}
C {/home/ricardo/RATT_repos/Proyectos_xschem/SNN/Inf_circuit.sym} -1990 -540 0 0 {name=x1}
C {/home/ricardo/RATT_repos/Proyectos_xschem/SNN/STDP_circuit.sym} -1990 -690 0 0 {name=x3}
C {/home/ricardo/RATT_repos/Proyectos_xschem/SNN/WU_Circuit.sym} -1990 -390 0 0 {name=x4}
C {devices/lab_pin.sym} -2050 -420 0 0 {name=p51 sig_type=std_logic lab=ctrl_wu}
C {devices/lab_pin.sym} -1940 -550 1 0 {name=p18 sig_type=std_logic lab=vpres2}
C {devices/lab_pin.sym} -1940 -400 1 0 {name=p19 sig_type=std_logic lab=vpres2}
C {devices/lab_pin.sym} -2040 -530 3 0 {name=p14 sig_type=std_logic lab=vpre2}
C {devices/lab_pin.sym} -2040 -680 3 0 {name=p20 sig_type=std_logic lab=vpre2}
